One B-rep face of a CAD part: STEP entity #289.
In plain terms, the cylindrical face has radius 35 mm (diameter 70 mm), a partial arc.
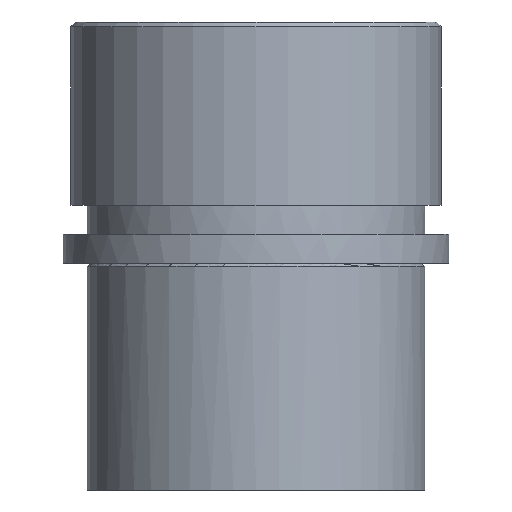
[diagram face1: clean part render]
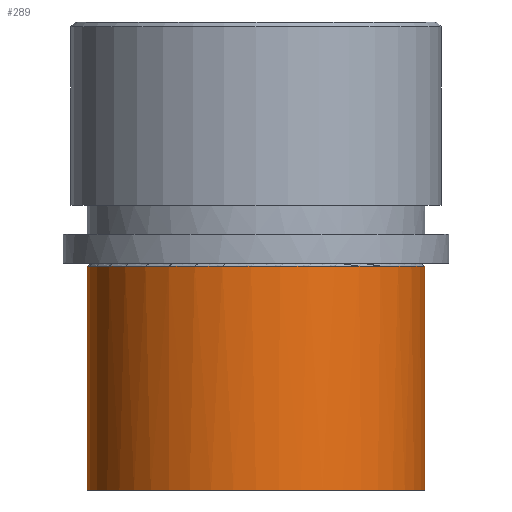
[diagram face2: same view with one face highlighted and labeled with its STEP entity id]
Its self-contained STEP definition (entity closure, numbers rounded to 3 decimals):
#109=CARTESIAN_POINT('Control Point',(-35.,0.,-47.)) ;
#110=CARTESIAN_POINT('Control Point',(-35.,-3.188,-47.)) ;
#111=CARTESIAN_POINT('Control Point',(-34.637,-6.376,-47.)) ;
#112=CARTESIAN_POINT('Control Point',(-33.911,-9.509,-47.)) ;
#113=CARTESIAN_POINT('Control Point',(-31.758,-15.555,-47.)) ;
#114=CARTESIAN_POINT('Control Point',(-28.302,-20.962,-47.)) ;
#115=CARTESIAN_POINT('Control Point',(-26.272,-23.456,-47.)) ;
#116=CARTESIAN_POINT('Control Point',(-21.679,-27.938,-47.)) ;
#117=CARTESIAN_POINT('Control Point',(-16.197,-31.274,-47.)) ;
#118=CARTESIAN_POINT('Control Point',(-13.276,-32.621,-47.)) ;
#119=CARTESIAN_POINT('Control Point',(-7.18,-34.626,-47.)) ;
#120=CARTESIAN_POINT('Control Point',(-0.79,-35.21,-47.)) ;
#121=CARTESIAN_POINT('Control Point',(2.426,-35.135,-47.)) ;
#122=CARTESIAN_POINT('Control Point',(8.782,-34.255,-47.)) ;
#123=CARTESIAN_POINT('Control Point',(14.778,-31.968,-47.)) ;
#124=CARTESIAN_POINT('Control Point',(17.633,-30.487,-47.)) ;
#125=CARTESIAN_POINT('Control Point',(22.955,-26.9,-47.)) ;
#126=CARTESIAN_POINT('Control Point',(27.334,-22.209,-47.)) ;
#127=CARTESIAN_POINT('Control Point',(29.246,-19.623,-47.)) ;
#128=CARTESIAN_POINT('Control Point',(32.284,-14.345,-47.)) ;
#129=CARTESIAN_POINT('Control Point',(34.122,-8.548,-47.)) ;
#130=CARTESIAN_POINT('Control Point',(34.707,-5.725,-47.)) ;
#131=CARTESIAN_POINT('Control Point',(35.,-2.863,-47.)) ;
#132=CARTESIAN_POINT('Control Point',(35.,0.,-47.)) ;
#133=CARTESIAN_POINT('Vertex',(-35.,0.,-47.)) ;
#135=CARTESIAN_POINT('Vertex',(35.,0.,-47.)) ;
#247=CARTESIAN_POINT('Axis2P3D Location',(0.,0.,50.)) ;
#252=CARTESIAN_POINT('Line Origine',(35.,0.,50.)) ;
#256=CARTESIAN_POINT('Vertex',(35.,0.,-0.6)) ;
#260=CARTESIAN_POINT('Control Point',(-35.,0.,-0.6)) ;
#261=CARTESIAN_POINT('Control Point',(-35.,-5.498,-0.6)) ;
#262=CARTESIAN_POINT('Control Point',(-33.921,-10.996,-0.6)) ;
#263=CARTESIAN_POINT('Control Point',(-31.76,-16.21,-0.6)) ;
#264=CARTESIAN_POINT('Control Point',(-25.512,-25.512,-0.6)) ;
#265=CARTESIAN_POINT('Control Point',(-16.21,-31.76,-0.6)) ;
#266=CARTESIAN_POINT('Control Point',(-10.996,-33.921,-0.6)) ;
#267=CARTESIAN_POINT('Control Point',(0.,-36.079,-0.6)) ;
#268=CARTESIAN_POINT('Control Point',(10.996,-33.921,-0.6)) ;
#269=CARTESIAN_POINT('Control Point',(16.21,-31.76,-0.6)) ;
#270=CARTESIAN_POINT('Control Point',(25.512,-25.512,-0.6)) ;
#271=CARTESIAN_POINT('Control Point',(31.76,-16.21,-0.6)) ;
#272=CARTESIAN_POINT('Control Point',(33.921,-10.996,-0.6)) ;
#273=CARTESIAN_POINT('Control Point',(35.,-5.498,-0.6)) ;
#274=CARTESIAN_POINT('Control Point',(35.,0.,-0.6)) ;
#275=CARTESIAN_POINT('Vertex',(-35.,0.,-0.6)) ;
#278=CARTESIAN_POINT('Line Origine',(-35.,0.,50.)) ;
#248=DIRECTION('Axis2P3D Direction',(0.,0.,-1.)) ;
#249=DIRECTION('Axis2P3D XDirection',(1.,0.,0.)) ;
#253=DIRECTION('Vector Direction',(0.,0.,-1.)) ;
#279=DIRECTION('Vector Direction',(0.,0.,-1.)) ;
#250=AXIS2_PLACEMENT_3D('Cylinder Axis2P3D',#247,#248,#249) ;
#284=ORIENTED_EDGE('',*,*,#258,.T.) ;
#285=ORIENTED_EDGE('',*,*,#277,.F.) ;
#286=ORIENTED_EDGE('',*,*,#282,.T.) ;
#287=ORIENTED_EDGE('',*,*,#137,.T.) ;
#254=VECTOR('Line Direction',#253,1.) ;
#280=VECTOR('Line Direction',#279,1.) ;
#289=ADVANCED_FACE('735-50',(#288),#251,.T.) ;
#108=B_SPLINE_CURVE_WITH_KNOTS('',5,(#109,#110,#111,#112,#113,#114,#115,#116,#117,#118,#119,#120,#121,#122,#123,#124,#125,#126,#127,#128,#129,#130,#131,#132),.UNSPECIFIED.,.F.,.U.,(6,3,3,3,3,3,3,6),(0.,22.543,45.086,67.629,90.172,112.716,135.259,155.5),.UNSPECIFIED.) ;
#259=B_SPLINE_CURVE_WITH_KNOTS('',5,(#260,#261,#262,#263,#264,#265,#266,#267,#268,#269,#270,#271,#272,#273,#274),.UNSPECIFIED.,.F.,.U.,(6,3,3,3,6),(-54.978,-27.489,0.,27.489,54.978),.UNSPECIFIED.) ;
#251=CYLINDRICAL_SURFACE('generated cylinder',#250,35.) ;
#137=EDGE_CURVE('',#134,#136,#108,.T.) ;
#258=EDGE_CURVE('',#136,#257,#255,.F.) ;
#277=EDGE_CURVE('',#276,#257,#259,.T.) ;
#282=EDGE_CURVE('',#276,#134,#281,.T.) ;
#283=EDGE_LOOP('',(#284,#285,#286,#287)) ;
#288=FACE_OUTER_BOUND('',#283,.T.) ;
#255=LINE('Line',#252,#254) ;
#281=LINE('Line',#278,#280) ;
#134=VERTEX_POINT('',#133) ;
#136=VERTEX_POINT('',#135) ;
#257=VERTEX_POINT('',#256) ;
#276=VERTEX_POINT('',#275) ;
